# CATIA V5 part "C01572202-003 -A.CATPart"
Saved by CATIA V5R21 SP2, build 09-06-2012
Part number: C01572202-003
Revision: ---
Description: PROPRIETARY NOTICE (do not delete / modify)  ***************************************************************************************************  LA SOCIETE EN COMMANDITE  AIRBUS CANADA  ("AIRBUS CANADA")  PAR  L'INTERMEDIAIRE  DE  SES  DIVISIONS  ET/OU  FILIALES  CORPORATIVES,  FOURNIT  LES PRESENTES  INFORMATIONS  AU  GOUVERNEMENT  A  TITRE CONFIDENTIEL. CES  INFORMATIONS ONT UNE TENEUR CONFIDENTIELLE,  AVEC DROITS DE PROPRIETE,  ET NOUS LES CONSIDERONS  EXCLUS  DE   L'APPLICATION  DE  LA LOI SUR L'ACCES A L'INFORMATION  (CANADA),  LES  LOIS  SUR  L'ACCES  A  L'INFORMATION  EUROPEENNES,  LE FREEDOM OF INFORMATION ACT (ETATS-UNIS) ET D'AUTRES LOIS SEMBLABLES. ELLES  PEUVENT  AUSSI  CONSTITUER DES SECRETS INDUSTRIELS DE NOTRE SOCIETE OU DE TIERCES PARTIES. LA DIVULGATION  PUBLIQUE  DE CES  INFORMATIONS NUIRAIT A AIRBUS CANADA OU A DES TIERCES PARTIES.  CES INFORMATIONS PEUVENT EGALEMENT CONTENIR  DES DONNEES QUI SONT CONTROLEE PAR DES LOIS DE CONTROLE DES EXPORTATIONS DU CANADA, L’EUROPE OU LES  ETATS-  UNIS. TOUTE EXPORTATION OU REEXPORTATION DE DONNEES CONTROLEES SANS AUTORISATION EST STRICTEMENT INTERDITE.  TOUTE INTENTION DE LES DIVULGUER EN TOUT OU EN PARTIE DEVRA ETRE SIGNIFIEE A L'AVANCE ET PAR ECRIT AU VICE-  PRESIDENT, SERVICES JURIDIQUES ET CONFORMITE ET SECRETAIRE CORPORATIF D'AIRBUS CANADA.    AIRBUS CANADA LIMITED PARTNERSHIP  ("AIRBUS CANADA"),  BY ITS AFFILIATES AND/OR SUBSIDIARIES, PROVIDES THIS  INFORMATION TO THE GOVERNMENT IN CONFIDENCE. THIS IS PROPRIETARY CONFIDENTIAL INFORMATION WHICH WE CONSIDER  EXCLUDED  FROM  THE  APPLICATION OF THE ACCESS TO INFORMATION ACT (CANADA),  THE FREEDOM OF INFORMATION ACT  (U.S.A.),  THE ACCESS TO INFORMATION LAWS IN EUROPE, AND OTHER SIMILAR LEGISLATION. AND MAY ALSO CONSTITUTE  TRADE SECRETS OF OUR  COMPANY OR THIRD PARTIES.  PUBLIC  RELEASE  OF  THIS INFORMATION  WOULD BE HARMFUL TO  AIRBUS CANADA OR THIRD PARTIES.  THIS  INFORMATION  MAY  ALSO  CONTAIN DATA THAT IS CONTROLLED BY CANADIAN,  EUROPEAN, OR U.S.A. EXPORT CONTROL LAWS. ANY UNAUTHORIZED EXPORT OR RE-EXPORT OF ANY EXPORT CONTROLLED DATA  IS STRICTLY PROHIBITED  ANY INTENTION TO DISCLOSE SUCH INFORMATION,  OR  PART THEREOF,  MUST BE NOTIFIED IN  ADVANCE AND IN WRITING TO THE VICE PRESIDENT, LEGAL AND COMPLIANCE AND CORPORATE SECRETARY OF AIRBUS CANADA.        LES RENSEIGNEMENTS,  LES DONNEES  ET  DESSINS  TECHNIQUES  DIVULGUES  DANS  LES PRESENTES SONT LA PROPRIETE  EXCLUSIVE DE LA SOCIETE EN COMMANDITE AIRBUS CANADA ("AIRBUS CANADA") OU COMPORTENT DES DROITS DE PROPRIETE  APPARTENANT  A  AUTRUI ET NE PEUVENT ETRE DIVULGUES  A  QUICONQUE  NI  UTILISES PAR QUI QUE CE SOIT SANS LE  CONSENTEMENT  ECRIT  D’AIRBUS  CANADA.  LE DETENTEUR DES  PRESENTES  S'ENGAGE, DANS TOUTES CIRCONSTANCES, A  GARDER CONFIDENTIELS LES DONNEES ET DESSINS TECHNIQUES QU'ELLES CONTIENNENT.   CE QUI PRECEDE NE S'APPLIQUE  PAS  AUX PERSONNES  QUI  ONT DES DROITS DE PROPRIETE SUR CES RENSEIGNEMENTS,  DONNEES TECHNIQUES ET DESSINS  DANS LA MESURE OU CES DROITS EXISTENT.    THE INFORMATION,  TECHNICAL DATA  AND  DESIGNS DISCLOSED HEREIN ARE THE EXCLUSIVE PROPERTY OF AIRBUS CANADA  LIMITED PARTNERSHIP  ("AIRBUS CANADA")  OR  CONTAIN PROPRIETARY RIGHTS OF OTHERS  AND ARE NOT TO BE USED OR  DISCLOSED  TO  OTHERS WITHOUT THE WRITTEN CONSENT OF AIRBUS CANADA.  THE RECIPIENT OF THIS DOCUMENT, BY ITS  RETENTION  AND  USE  AGREES TO  HOLD  IN  CONFIDENCE  THE  TECHNICAL DATA AND DESIGNS CONTAINED HEREIN. THE  FOREGOING SHALL NOT APPLY TO PERSONS HAVING PROPRIETARY RIGHTS TO SUCH INFORMATION,  TECHNICAL DATA OR SUCH  DESIGNS TO THE EXTENT THAT SUCH RIGHTS EXIST.    Copyright 2020 Airbus Canada Limited Partnership. All Rights Reserved.  ***********************************
Property "Title": "CRANK, CAM SHAFT, OWE"
Property "Dataset Type": "DETAIL"
Property "Supplier Name And CAGE Code": "AIRBUS CANADA LIMITED PARTNERSHIP L0J48"
Property "Major Supplier Code": "LP"
Property "3D Only": "Y"
Property "Material Form": "BAR - ROUND"
Property "Finish Code": "T002"
Property "PCCN": "2"
Property "TD Material Code": "-"
Property "Organization": "DESIGN"
Property "Design Authority Program": "BD-500"
Property "Color Coded": "N"
Property "Thickness": 0
Property "Inside Diameter": 0
Property "Outside Diameter": 5
Property "Length": 0
Property "Width": 0
Property "Wall": 0
Property "Alloy": "6AL-4V"
Property "Final Condition": "ANL"
Property "MFG Process": "MACHINED"
Property "Material Specification Production": "AMS4928"
Property "Material Description Production": "TITANIUM"
Property "Dimensions": "DIMENSIONS ARE IN INCHES"
Property "Roughness": "ALL MACHINED SURFACES 125 Ra MAX"
Property "Eng. Tolerances": "LINEAR .XX= +/-.03; .XXX= +/-.010; ANGULAR= +/-0.5 DEG"
Property "Tool Design Tolerances": "LINEAR .X= +/-.06; .XX= +/-.015; .XXX= +/-.005; .XXXX= +/-.001; ANGULAR= +/-0.5 DEG"
Property "Project": "BA"
Publications: "PartBody", "Extract.1-DATUM_A", "Extract.2-DATUM_B", "Extract.3-DATUM_C"
Material "TI-6AL-4V": density 4428.78 kg/m3, Young's modulus 1.11695e+11 Pa, Poisson ratio 0.31
Bounding box of the stored display mesh (mm): x -76.2 to 37.389, y -24.277 to 20.458, z -20.458 to 61.276
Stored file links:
  C:\Users\CQQZ006\Desktop\A220钢钛件\舱门\C01572202-003\C01572202-003 -A.CATPart

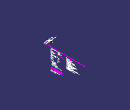
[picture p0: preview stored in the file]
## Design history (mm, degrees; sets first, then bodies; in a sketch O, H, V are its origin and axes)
AxisSystem1 "Absolute Axis System": origin (0, 0, 0), X (1, 0, 0), Y (0, 1, 0), Z (0, 0, 1)
Part_3D_Annotations1 "CATTPSSet"
Set1 "Pilot_Holes"
  Plane1: type Angle, RefPlane Plane2, Direction X axis, Angle 90
  Plane2: type Angle, RefPlane zx-plane, Direction X axis, Angle 63.5
  Point1: (-55.88, 0, 0), in AxisSystem1
  Point2: (-68.58, 0, 0), in AxisSystem1
  Line1: type Normal, RefPoint Point1, RefSkin Plane1, Start 22.86, End -22.86
  Line2: type Normal, RefPoint Point2, RefSkin Plane2, Start 22.86, End -22.86
Set2 "Master_Geometry"
  Extract1 "Extract.1-DATUM_A": ExtractElem face of Shaft1 from Sketch1.L3
  Extract2 "Extract.2-DATUM_B": ExtractElem face of Shaft1 from Sketch1.L4
  Extract3 "Extract.3-DATUM_C": ExtractElem face of Pocket1 from Sketch2.A4
Set3 "References"
  DatumSurface1
Set5 "Construction_Geometry"
  Plane3: type Angle, RefPlane zx-plane, Direction X axis, Angle 31.5
Body1 "PartBody" (main body)
  Sketch1 on zx-plane, origin (0, 0, 0), H (-1, 0, 0), V (0, 0, 1)
    line L1 (76.2, 7.1153) -> (76.2, 9.144)
    line L2 (76.2, 9.144) -> (41.9383, 9.144)
    line L3 (40.64, 9.5009) -> (-3.048, 9.5009)
    line L4 (-3.81, 10.2629) -> (-3.81, 15.24)
    line L5 (-3.81, 15.24) -> (-4.826, 15.24)
    arc A1 centre (-4.826, 21.59) radius 6.35 from (-4.826, 15.24) to (-9.8861, 17.7536) cw
    point P2 (-4.826, 21.59)
    line L6 (-21.7678, 35.56) -> (-21.7678, 78.74)
    line L7 (-21.7678, 78.74) -> (-37.3888, 78.74)
    line L8 (-37.3888, 78.74) -> (-37.3888, 12.7)
    line L9 (-37.3888, 12.7) -> (-8.382, 12.7)
    arc A2 centre (-8.382, 11.176) radius 1.524 from (-8.382, 12.7) to (-6.858, 11.176) cw
    line L10 (-6.858, 11.176) -> (-6.858, 7.62)
    line L11 (38.1502, 7.1153) -> (76.2, 7.1153)
    construction line L12 (-107.0731, 0) -> (-83.8961, 0)
    point P9 (-107.0731, 0)
    arc A3 centre (41.9383, 11.684) radius 2.54 from (41.9383, 9.144) to (40.64, 9.5009) cw
    point P13 (40.64, 9.5009)
    line L13 (-5.842, 6.604) -> (36.1918, 6.604)
    line L14 (36.1918, 6.604) -> (38.0515, 7.1023)
    point P15 (38.1, 7.1153)
    line L15 (-6.858, 7.62) -> (-5.842, 6.604)
    point P17 (-5.842, 6.604)
    arc A4 centre (-3.048, 10.2629) radius 0.762 from (-3.048, 9.5009) to (-3.81, 10.2629) cw
    arc A5 centre (-15.4178, 35.56) radius 6.35 from (-20.4779, 31.7236) to (-21.7678, 35.56) cw
    point P21 (-15.4178, 35.56)
    line L16 (-9.8861, 17.7536) -> (-20.4779, 31.7236)
    axis line L17 (-144.5617, 0) -> (164.8898, 0)
    arc A6 centre (38.1502, 6.7343) radius 0.381 from (38.1502, 7.1153) to (38.0515, 7.1023) ccw
    distance L12 L11 = 7.1153
    distance L2 L12 = 9.144
    distance L3 L12 = 9.5009
    distance L5 L12 = 15.24
    radius A1 = 6.35
    radius A2 = 1.524
    distance L9 L12 = 12.7
    radius A3 = 2.54
    distance L13 L12 = 6.604
    distance P17 L10 = 1.016
    radius A4 = 0.762
    distance P2 L4 = 1.016
    radius A5 = 6.35
    distance P21 L12 = 35.56
    distance H L7 = 78.74
    distance A2 A1 = 3.1304 (reference)
    distance L6 L8 = 15.621
    distance L10 L4 = 3.048
    angle L14 L11 = 15
    distance L4 V = 3.81
    distance L4 L1 = 80.01
    distance L4 P13 = 44.45
    distance P15 L1 = 38.1
    angle L15 L13 = 45
    distance L4 L6 = 17.9578
    radius A6 = 0.381
    vertical: L1 V, L4 V, L8 V, L6 V, L10 V
    horizontal: L2 H, L3 H, L5 H, L7 H, L9 H, L11 H, L12 H, L13 H
    tangency: A2 L9, L10 A2, A3 L2, A4 L3, A4 L4, L5 A1, A5 L6, L16 A1, A5 L16, A6 L11, A6 L14
    coincidence: P9 H, L17 H, L11 P15, L14 P15
  Shaft1: profile Sketch1, axis Sketch1.L17, angle 360
  Sketch2 on yz-plane, origin (0, 0, 0), H (0, 1, 0), V (0, 0, 1)
    construction line L1 (0, 0) -> (0, 53.34)
    arc A1 centre (0, 53.34) radius 7.9375 from (7.3065, 50.2386) to (-6.7314, 57.5462) ccw
    arc A2 centre (0, 0) radius 15.24 from (-14.4097, -4.9617) to (13.0632, 7.8492) ccw
    arc A3 centre (9.0986, 31.7083) radius 8.89 from (0.9153, 35.1819) to (1.4784, 27.1296) ccw
    line L2 (13.0632, 7.8492) -> (1.4784, 27.1296)
    circle A4 centre (0, 53.34) radius 3.175
    line L3 (0.9153, 35.1819) -> (7.3065, 50.2386)
    line L4 (-14.4097, -4.9617) -> (-23.5863, 21.6891)
    arc A5 centre (-11.5782, 25.8238) radius 12.7 from (-23.5863, 21.6891) to (-22.3484, 32.5538) cw
    line L5 (-22.3484, 32.5538) -> (-6.7314, 57.5462)
    radius A1 = 7.9375
    length L1 = 53.34
    radius A2 = 15.24
    radius A3 = 8.89
    angle L1 L2 = 31
    radius A4 = 3.175
    radius A5 = 12.7
    angle L5 L3 = 9
    angle L1 L4 = 19
    angle L1 L3 = 23
    tangency: L2 A2, L2 A3, L3 A1, A3 L3, L4 A2, A5 L4, L5 A1, L5 A5
    vertical: L1 V
  Pocket1: profile Sketch2, direction (1, 0, 0), length 50.8, opposite side length 1.27, outer side
  Sketch3 on Plane3, origin (0, 0, 0), H (-1, 0, 0), V (0, -0.5225, 0.8526)
    line L1 (-63.5, 59.8462) -> (-3.81, -25.4)
    line L2 (-3.81, -25.4) -> (-63.5, -25.4)
    line L3 (-63.5, -25.4) -> (-63.5, 59.8462)
    reference intersected line E1 through (0, 0) direction (-1, 0) from xy-plane
    point P3 (-3.81, -25.4)
    reference intersected line E2 through (0, 0) direction (0, -1) from yz-plane
    distance E1 L2 = 25.4
    distance E2 P3 = 3.81
    distance L3 V = 63.5
    angle L1 H = 125
    horizontal: L2 H
    vertical: L3 V
  Pocket2: profile Sketch3, direction (0, -0.8526, -0.5225), length 50.8, mirrored extent
  Body2
    Sketch4 on YZ plane of AxisSystem1, origin (0, 0, 0), H (0, 1, 0), V (0, 0, 1)
      point P1 (0, 0)
      reference projected point E1 (0, 0) from vertex [YZ plane of AxisSystem1 | ZX plane of AxisSystem1 | XY plane of AxisSystem1]
      line L1 (-54.3233, 78.74) -> (25.4, 11.8442)
      line L2 (25.4, 11.8442) -> (25.4, 78.74)
      line L3 (25.4, 78.74) -> (-54.3233, 78.74)
      reference projected point E2 (0, 53.34) from axis of face of Pocket1 from Sketch2.A4
      construction line L4 (0, 53.34) -> (0, 0)
      angle L4 L1 = 50
      distance O L1 = 25.4
      distance E2 L3 = 25.4
      distance E2 L2 = 25.4
      coincidence: E1 P1
      vertical: L4 V, L2 V
      horizontal: L3 H
    Pocket3: profile Sketch4, direction (1, 0, 0), up to face of Shaft1 from Sketch1.L6, offset -3.048, opposite side up to face of Shaft1 from Sketch1.L8, offset -3.048
    Fillet1: radius 1.524, on edge [face of Pocket3 from Sketch4.L1 | start face of Pocket3]; edge [end face of Pocket3 | face of Pocket3 from Sketch4.L1]
  Assemble1: tool Body2
  Sketch5 on yz-plane, origin (0, 0, 0), H (0, 1, 0), V (0, 0, 1)
    line L1 (-21.1847, 22.516) -> (-16.5307, 8.9998)
    line L2 (10.563, 7.0786) -> (-0.6988, 25.8214)
    line L3 (-4.3274, 33.4727) -> (-8.2122, 36.7325)
    point P1 (-33.3398, 57.817)
    arc A1 centre (-8.4091, 28.6083) radius 6.35 from (-4.3274, 33.4727) to (-2.1563, 29.7154) cw
    projected circle E1 centre (0, 0) radius 12.7 from edge [face of Shaft1 from Sketch1.L9 | face of Shaft1 from Sketch1.A2]
    reference projected line E2 (13.0632, 7.8492) -> (1.4784, 27.1296) from edge [face of Pocket1 from Sketch2.L2 | face of Pocket2 from Sketch3.L1]
    reference projected line E3 (-14.4097, -4.9617) -> (-20.8314, 13.6882) from edge [face of Pocket2 from Sketch3.L1 | face of Pocket1 from Sketch2.L4]
    reference projected line E4 (-14.4137, 45.2519) -> (0.2907, 32.9134) from edge [face of Pocket3 from Sketch4.L1 | face of Fillet1]
    line L4 (-16.5307, 8.9998) -> (10.563, 7.0786)
    arc A2 centre (-12.294, 31.8681) radius 6.35 from (-8.2122, 36.7325) to (-17.6791, 35.2331) ccw
    reference projected line E6 (-6.7314, 57.5462) -> (-22.3484, 32.5538) from face of Pocket1 from Sketch2.L5
    line L5 (-17.6791, 35.2331) -> (-20.1944, 31.2078)
    offset arc E7 centre (-11.5782, 25.8238) radius 10.16 from (-20.1944, 31.2078) to (-21.1847, 22.516) ccw from face of Pocket1 from Sketch2.A5
    offset arc E8 centre (-11.5782, 25.8238) radius 10.16 from (-20.1944, 31.2078) to (-21.1847, 22.516) ccw from face of Pocket1 from Sketch2.A5
    offset arc E10 centre (9.0986, 31.7083) radius 11.43 from (-1.4228, 36.1743) to (-0.6988, 25.8214) ccw from face of Pocket1 from Sketch2.A3
    offset arc E11 centre (9.0986, 31.7083) radius 11.43 from (-2.1563, 29.7154) to (-0.6988, 25.8214) ccw from face of Pocket1 from Sketch2.A3
    radius A1 = 6.35
    distance E3 L1 = 2.54
    distance L2 E2 = 2.54 (reference)
    distance L3 E4 = 2.54
    radius A2 = 6.35
    distance L5 E6 = 2.54 (reference)
    coincidence: P1 L1, L3 P1
    tangency: A1 L3, L3 A2, A2 L5, E7 L5, E10 L2, A1 E10
  Pocket4: profile Sketch5, direction (1, 0, 0), length 50.8, opposite side length -23.8163
  Fillet2: radius 1.524, on edge [face of Pocket4 from Sketch5.L1 | start face of Pocket4]; edge [face of Pocket4 from Sketch5.A2 | start face of Pocket4]; edge [face of Pocket4 from Sketch5.L3 | start face of Pocket4]; edge [face of Pocket4 from Sketch5.A1 | start face of Pocket4]; edge [face of Pocket4 | start face of Pocket4]
  Sketch6 on face of Shaft1 from Sketch1.L8, origin (37.3888, 0, 78.74), H (0, 1, 0), V (0, 0, -1)
    circle A1 centre (0, 25.4) radius 4.7625
    reference projected circle E1 centre (0, 25.4) radius 3.175 from edge [face of Pocket1 from Sketch2.A4 | face of Shaft1 from Sketch1.L8]
    radius A1 = 4.7625
    concentricity: A1 E1
  Pocket5: profile Sketch6, direction (-1, 0, 0), length 3.81
  Body3
    Sketch7 on yz-plane, origin (0, 0, 0), H (0, 1, 0), V (0, 0, 1)
      line L1 (10.886, 6.541) -> (-4.4679, 32.0942)
      point P1 (-11.4094, 21.7332)
      arc A1 centre (-9.9109, 28.8237) radius 6.35 from (-11.9757, 34.8286) to (-4.4679, 32.0942) cw
      projected circle E1 centre (0, 0) radius 12.7 from edge [face of Shaft1 from Sketch1.L9 | face of Shaft1 from Sketch1.A2]
      projected arc E2 centre (0, 0) radius 12.7 from (-12.0081, -4.1347) to (10.886, 6.541) ccw from edge [face of Shaft1 from Sketch1.L9 | face of Shaft1 from Sketch1.A2]
      reference projected line E3 (-14.4097, -4.9617) -> (-20.8314, 13.6882) from edge [face of Pocket2 from Sketch3.L1 | face of Pocket1 from Sketch2.L4]
      reference projected line E4 (13.0632, 7.8492) -> (1.4784, 27.1296) from edge [face of Pocket1 from Sketch2.L2 | face of Pocket2 from Sketch3.L1]
      reference projected line E5 (-14.4137, 45.2519) -> (0.2907, 32.9134) from edge [face of Pocket3 from Sketch4.L1 | face of Fillet1]
      line L2 (-20.6515, 20.9676) -> (-12.0081, -4.1347)
      arc A2 centre (0, 0) radius 36.83 from (-11.9757, 34.8286) to (-15.2527, 33.5232) ccw
      point P12 (0, 0)
      arc A3 centre (-11.0451, 24.2754) radius 10.16 from (-20.6515, 20.9676) to (-15.2527, 33.5232) cw
      line L3 (-114.3, 114.3) -> (114.3, 114.3)
      line L4 (114.3, 114.3) -> (114.3, -114.3)
      line L5 (114.3, -114.3) -> (-114.3, -114.3)
      line L6 (-114.3, -114.3) -> (-114.3, 114.3)
      radius A1 = 6.35
      distance E4 L1 = 2.54
      distance L2 E3 = 2.54
      radius A2 = 36.83
      radius A3 = 10.16
      distance H L5 = 114.3
      distance V L4 = 114.3
      distance A1 E5 = 3.3404 (reference)
      tangency: A1 L1, A1 A2, A3 A2, L2 A3
      coincidence: P12 O
      horizontal: L3 H, L5 H
      vertical: L4 V, L6 V
      symmetry: L6 L4 V, L3 L5 H
    Sketch8 on zx-plane, origin (0, 0, 0), H (-1, 0, 0), V (0, 0, 1)
      axis line L1 (-102.5955, 0) -> (138.1111, 0)
      point P1 (-102.5955, 0)
      reference projected line E1 (-9.8861, 17.7536) -> (-20.4779, 31.7236) from Sketch1.L16
      line L2 (-50.8, 68.3535) -> (-11.5053, 16.5259)
      point P5 (-50.8, 68.3535)
      reference projected arc E3 centre (-4.826, 21.59) radius 6.35 from (-9.8861, 17.7536) to (-4.826, 15.24) ccw from Sketch1.A1
      reference projected line E4 (-3.81, 10.2629) -> (-3.81, 15.24) from Sketch1.L4
      arc A1 centre (-4.826, 21.59) radius 8.382 from (-11.5053, 16.5259) to (-6.858, 13.458) ccw
      point P12 (-4.826, 21.59)
      line L3 (-6.858, 13.458) -> (-6.858, 0)
      point P14 (-6.858, 0)
      line L4 (-50.8, 68.3535) -> (-50.8, 0)
      point P15 (-50.8, 0)
      distance L2 E1 = 2.032
      distance P5 V = 50.8
      distance E4 L3 = 3.048
      coincidence: P1 H, P14 L1, P15 L1
      horizontal: L1 H
      concentricity: P12 E3
      tangency: A1 L2
      vertical: L3 V, L4 V
    Groove1: profile Sketch8, axis Sketch8.L1, angle 360
    Pad1: profile Sketch7, direction (1, 0, 0), length 63.5
    Fillet3: radius 6.35, on edge [face of Groove1 from Sketch8.L2 | face of Pad1 from Sketch7.L1]
    Fillet4: radius 1.524, on edge [face of Pad1 from Sketch7.E2 | face of Groove1 from Sketch8.L3]
  Assemble2: tool Body3
  Chamfer1: length 0.381, second length 0.381, on edge [face of Shaft1 from Sketch1.L1 | face of Shaft1 from Sketch1.L11]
